One B-rep face of a CAD part: STEP entity #794.
In plain terms, the planar face has unit normal (1, 0, 0).
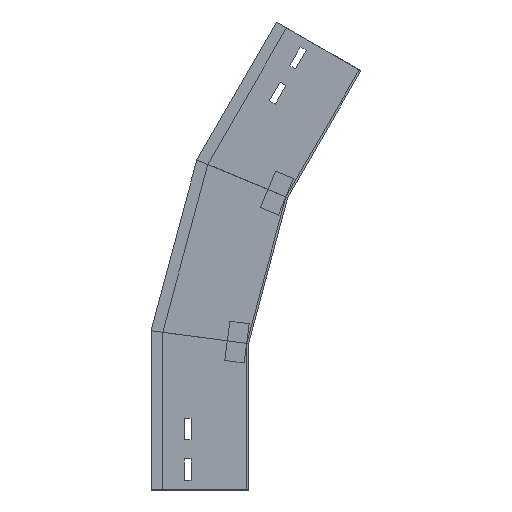
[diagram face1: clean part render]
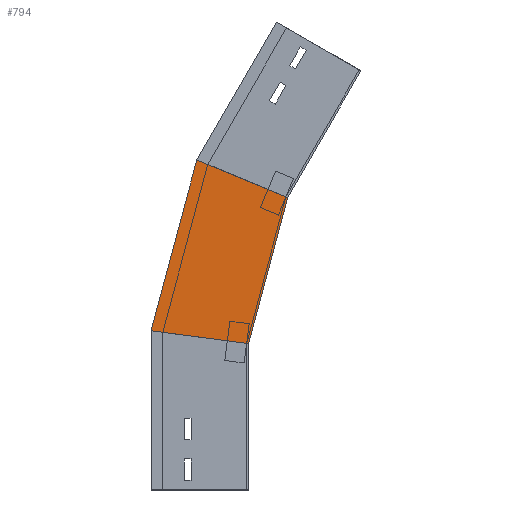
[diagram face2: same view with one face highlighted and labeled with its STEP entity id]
Its self-contained STEP definition (entity closure, numbers rounded to 3 decimals):
#48 = VERTEX_POINT ( 'NONE', #440 ) ;
#60 = CARTESIAN_POINT ( 'NONE',  ( 0., 3.774, 135.915 ) ) ;
#64 = VECTOR ( 'NONE', #458, 1000. ) ;
#114 = LINE ( 'NONE', #1043, #1441 ) ;
#341 = LINE ( 'NONE', #685, #64 ) ;
#361 = EDGE_CURVE ( 'NONE', #48, #1425, #341, .T. ) ;
#380 = DIRECTION ( 'NONE',  ( 0., -0.259, 0.966 ) ) ;
#436 = ORIENTED_EDGE ( 'NONE', *, *, #881, .T. ) ;
#440 = CARTESIAN_POINT ( 'NONE',  ( 0., 0., 150. ) ) ;
#458 = DIRECTION ( 'NONE',  ( 0., -0.259, 0.966 ) ) ;
#467 = CARTESIAN_POINT ( 'NONE',  ( 0., 100.367, 161.797 ) ) ;
#516 = DIRECTION ( 'NONE',  ( 0., 0., -1. ) ) ;
#523 = DIRECTION ( 'NONE',  ( 1., 0., 0. ) ) ;
#547 = CARTESIAN_POINT ( 'NONE',  ( 0., -40.117, 299.719 ) ) ;
#566 = VECTOR ( 'NONE', #380, 1000. ) ;
#616 = VECTOR ( 'NONE', #1146, 1000. ) ;
#653 = DIRECTION ( 'NONE',  ( 0., -0.991, -0.131 ) ) ;
#685 = CARTESIAN_POINT ( 'NONE',  ( 0., 3.774, 135.915 ) ) ;
#688 = CARTESIAN_POINT ( 'NONE',  ( 0., 53.068, 338.317 ) ) ;
#740 = VERTEX_POINT ( 'NONE', #1447 ) ;
#794 = ADVANCED_FACE ( 'NONE', ( #1105 ), #882, .T. ) ;
#797 = ORIENTED_EDGE ( 'NONE', *, *, #1464, .F. ) ;
#801 = CARTESIAN_POINT ( 'NONE',  ( 0., -60.567, 291.248 ) ) ;
#831 = VERTEX_POINT ( 'NONE', #688 ) ;
#881 = EDGE_CURVE ( 'NONE', #740, #831, #1279, .T. ) ;
#882 = PLANE ( 'NONE',  #1292 ) ;
#1024 = LINE ( 'NONE', #801, #616 ) ;
#1043 = CARTESIAN_POINT ( 'NONE',  ( 0., -19.411, 147.444 ) ) ;
#1105 = FACE_OUTER_BOUND ( 'NONE', #1382, .T. ) ;
#1146 = DIRECTION ( 'NONE',  ( 0., -0.924, -0.383 ) ) ;
#1152 = ORIENTED_EDGE ( 'NONE', *, *, #361, .F. ) ;
#1279 = LINE ( 'NONE', #467, #566 ) ;
#1292 = AXIS2_PLACEMENT_3D ( 'NONE', #60, #523, #516 ) ;
#1382 = EDGE_LOOP ( 'NONE', ( #436, #1423, #1152, #797 ) ) ;
#1423 = ORIENTED_EDGE ( 'NONE', *, *, #1433, .T. ) ;
#1425 = VERTEX_POINT ( 'NONE', #547 ) ;
#1433 = EDGE_CURVE ( 'NONE', #831, #1425, #1024, .T. ) ;
#1441 = VECTOR ( 'NONE', #653, 1000. ) ;
#1447 = CARTESIAN_POINT ( 'NONE',  ( 0., 100., 163.165 ) ) ;
#1464 = EDGE_CURVE ( 'NONE', #740, #48, #114, .T. ) ;
